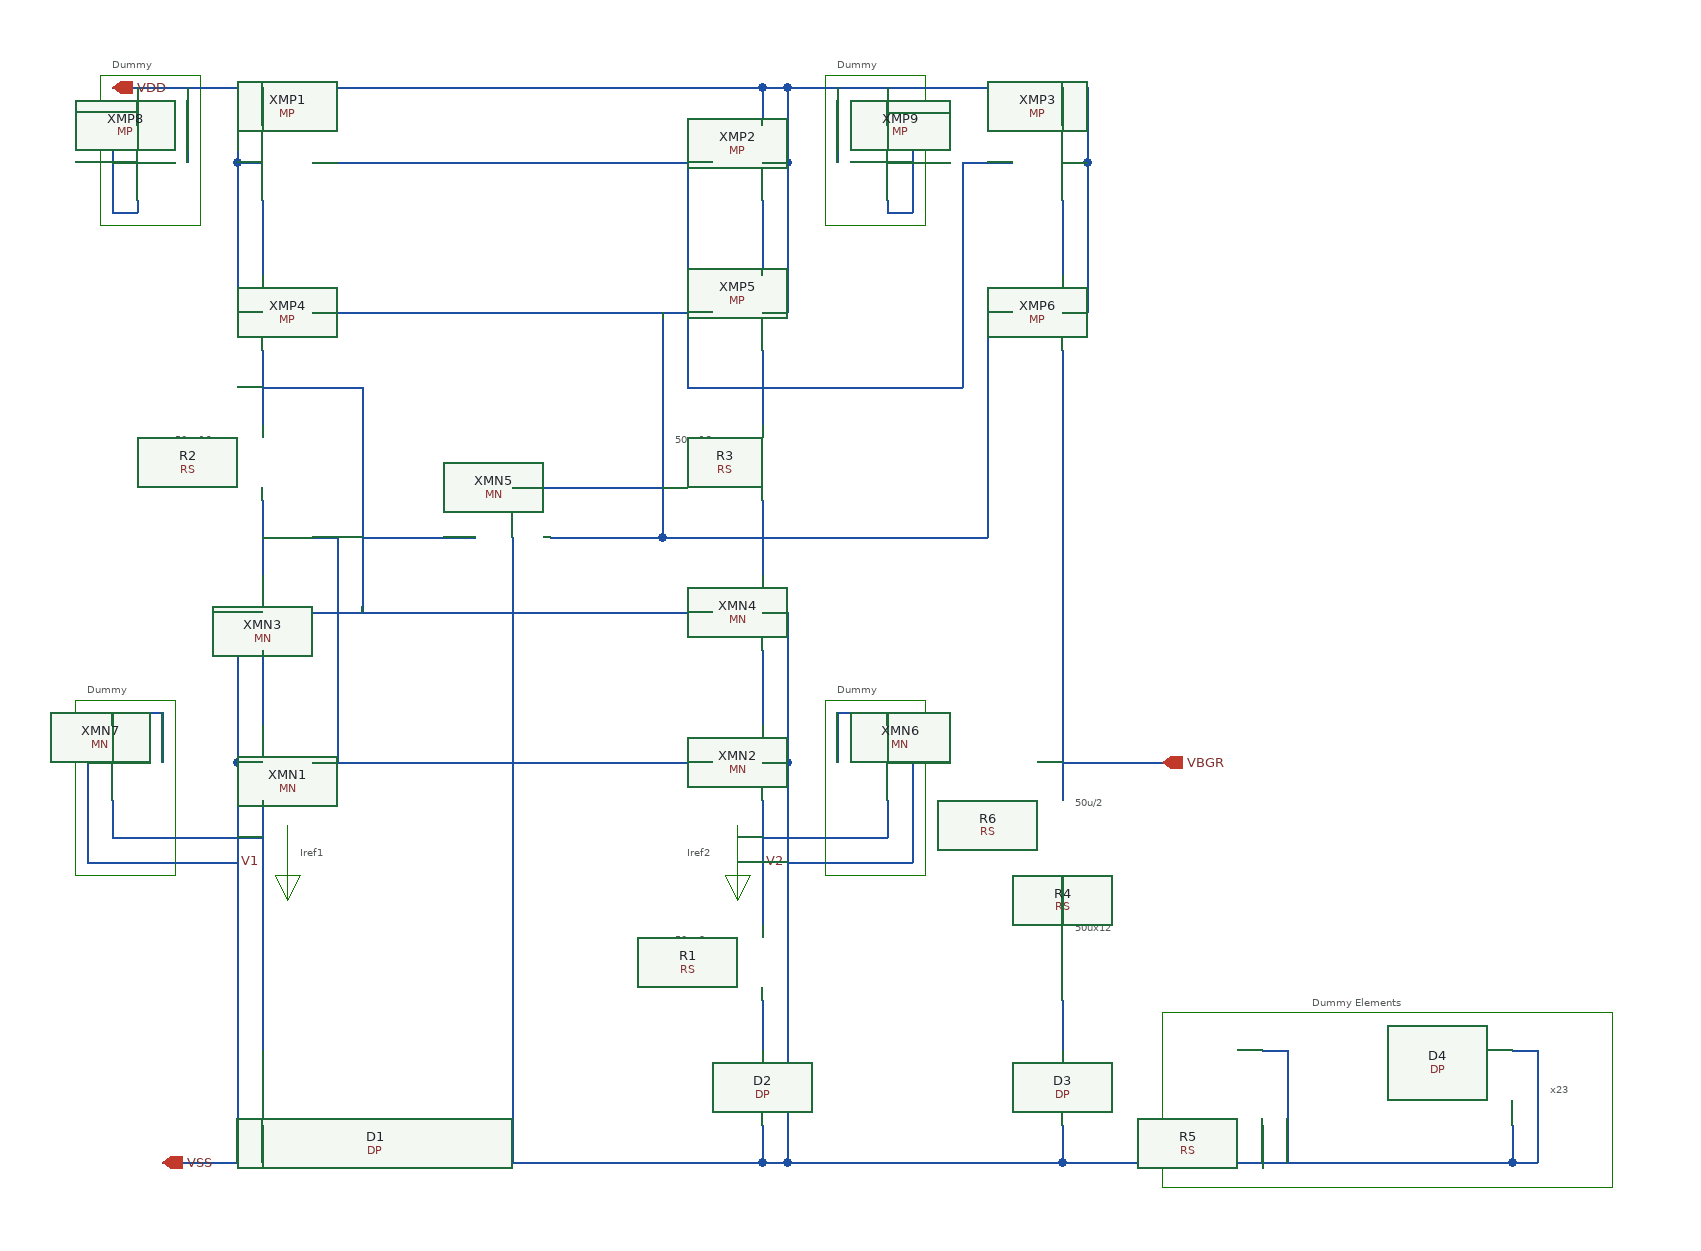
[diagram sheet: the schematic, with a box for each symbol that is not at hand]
v {xschem version=3.4.8RC file_version=1.2}
G {}
K {}
V {}
S {}
E {}
P 4 5 180 -290 180 -230 190 -250 170 -250 180 -230 {}
P 4 5 540 -290 540 -230 550 -250 530 -250 540 -230 {}
P 4 5 880 -140 880 0 1240 0 1240 -140 880 -140 {}
P 4 5 610 -390 610 -250 690 -250 690 -390 610 -390 {}
P 4 5 10 -390 10 -250 90 -250 90 -390 10 -390 {}
P 4 5 30 -890 30 -770 110 -770 110 -890 30 -890 {}
P 4 5 610 -890 610 -770 690 -770 690 -890 610 -890 {}
T {Iref1} 190 -280 0 0 0.25 0.25 {}
T {Iref2} 500 -280 0 0 0.25 0.25 {}
T {x8} 590 -90 0 0 0.25 0.25 {}
T {x8} 830 -90 0 0 0.25 0.25 {}
T {50ux2} 490 -210 0 0 0.25 0.25 {}
T {50ux16} 490 -610 0 0 0.25 0.25 {}
T {50ux16} 90 -610 0 0 0.25 0.25 {}
T {50ux12} 810 -220 0 0 0.25 0.25 {}
T {x23} 1190 -90 0 0 0.25 0.25 {}
T {Dummy Elements} 1000 -160 0 0 0.25 0.25 {}
T {Dummy} 620 -410 0 0 0.25 0.25 {}
T {Dummy} 20 -410 0 0 0.25 0.25 {}
T {Dummy} 40 -910 0 0 0.25 0.25 {}
T {Dummy} 620 -910 0 0 0.25 0.25 {}
T {50u/2} 810 -320 0 0 0.25 0.25 {}
N 560 -880 560 -850 {lab=VDD}
N 80 -880 560 -880 {lab=VDD}
N 160 -880 160 -850 {lab=VDD}
N 560 -820 580 -820 {lab=VDD}
N 580 -880 580 -820 {lab=VDD}
N 560 -880 580 -880 {lab=VDD}
N 140 -820 160 -820 {lab=VDD}
N 140 -880 140 -820 {lab=VDD}
N 200 -820 520 -820 {lab=#net1}
N 160 -310 160 -260 {lab=V1}
N 560 -310 560 -260 {lab=V2}
N 560 -340 580 -340 {lab=VSS}
N 580 -340 580 -300 {lab=VSS}
N 140 -340 160 -340 {lab=VSS}
N 140 -340 140 -300 {lab=VSS}
N 200 -340 520 -340 {lab=#net2}
N 220 -520 220 -340 {lab=#net2}
N 160 -520 220 -520 {lab=#net2}
N 500 -820 500 -780 {lab=#net1}
N 500 -780 500 -760 {lab=#net1}
N 500 -640 560 -640 {lab=#net1}
N 560 -260 560 -210 {lab=V2}
N 560 -150 560 -110 {lab=#net3}
N 160 -260 160 -110 {lab=V1}
N 560 -50 560 -20 {lab=VSS}
N 80 -20 560 -20 {lab=VSS}
N 160 -50 160 -20 {lab=VSS}
N 560 -640 720 -640 {lab=#net1}
N 720 -820 720 -640 {lab=#net1}
N 720 -820 760 -820 {lab=#net1}
N 580 -880 820 -880 {lab=VDD}
N 820 -880 820 -820 {lab=VDD}
N 800 -820 820 -820 {lab=VDD}
N 800 -880 800 -850 {lab=VDD}
N 800 -670 800 -600 {lab=VBGR}
N 160 -790 160 -730 {lab=#net4}
N 560 -790 560 -730 {lab=#net5}
N 200 -700 520 -700 {lab=#net6}
N 160 -430 160 -370 {lab=#net7}
N 560 -430 560 -370 {lab=#net8}
N 560 -460 580 -460 {lab=VSS}
N 200 -460 520 -460 {lab=#net9}
N 140 -460 160 -460 {lab=VSS}
N 560 -670 560 -610 {lab=#net1}
N 560 -700 580 -700 {lab=VDD}
N 140 -700 160 -700 {lab=VDD}
N 480 -700 480 -520 {lab=#net6}
N 480 -520 560 -520 {lab=#net6}
N 240 -640 240 -460 {lab=#net9}
N 160 -640 240 -640 {lab=#net9}
N 580 -740 580 -700 {lab=VDD}
N 140 -740 140 -700 {lab=VDD}
N 140 -460 140 -420 {lab=VSS}
N 580 -460 580 -420 {lab=VSS}
N 140 -820 140 -740 {lab=VDD}
N 580 -820 580 -740 {lab=VDD}
N 140 -420 140 -340 {lab=VSS}
N 580 -420 580 -340 {lab=VSS}
N 140 -300 140 -20 {lab=VSS}
N 580 -300 580 -20 {lab=VSS}
N 560 -20 580 -20 {lab=VSS}
N 160 -670 160 -610 {lab=#net9}
N 160 -550 160 -490 {lab=#net2}
N 560 -550 560 -490 {lab=#net6}
N 500 -760 500 -640 {lab=#net1}
N 800 -790 800 -730 {lab=#net10}
N 560 -520 740 -520 {lab=#net6}
N 800 -700 820 -700 {lab=VDD}
N 820 -820 820 -700 {lab=VDD}
N 740 -700 760 -700 {lab=#net6}
N 740 -700 740 -520 {lab=#net6}
N 800 -150 800 -110 {lab=#net11}
N 800 -50 800 -20 {lab=VSS}
N 580 -20 800 -20 {lab=VSS}
N 800 -600 800 -310 {lab=VBGR}
N 800 -340 880 -340 {lab=VBGR}
N 390 -520 480 -520 {lab=#net6}
N 360 -560 480 -560 {lab=#net6}
N 240 -520 330 -520 {lab=#net9}
N 360 -520 360 -20 {lab=VSS}
N 800 -20 1160 -20 {lab=VSS}
N 1160 -50 1160 -20 {lab=VSS}
N 1160 -110 1180 -110 {lab=VSS}
N 1180 -110 1180 -20 {lab=VSS}
N 1160 -20 1180 -20 {lab=VSS}
N 620 -380 620 -340 {lab=VSS}
N 660 -340 680 -340 {lab=VSS}
N 580 -260 680 -260 {lab=VSS}
N 80 -380 80 -340 {lab=VSS}
N 20 -340 40 -340 {lab=VSS}
N 20 -380 20 -260 {lab=VSS}
N 40 -310 40 -280 {lab=V1}
N 40 -280 160 -280 {lab=V1}
N 20 -260 140 -260 {lab=VSS}
N 40 -380 40 -370 {lab=VSS}
N 20 -380 80 -380 {lab=VSS}
N 660 -380 660 -370 {lab=VSS}
N 620 -380 680 -380 {lab=VSS}
N 680 -380 680 -260 {lab=VSS}
N 660 -310 660 -280 {lab=V2}
N 560 -280 660 -280 {lab=V2}
N 40 -880 80 -880 {lab=VDD}
N 60 -880 60 -850 {lab=VDD}
N 60 -790 60 -780 {lab=VDD}
N 40 -780 60 -780 {lab=VDD}
N 40 -860 40 -780 {lab=VDD}
N 40 -860 60 -860 {lab=VDD}
N 100 -880 100 -820 {lab=VDD}
N 40 -820 60 -820 {lab=VDD}
N 660 -880 660 -850 {lab=VDD}
N 660 -790 660 -780 {lab=VDD}
N 660 -780 680 -780 {lab=VDD}
N 680 -860 680 -780 {lab=VDD}
N 660 -860 680 -860 {lab=VDD}
N 620 -880 620 -820 {lab=VDD}
N 660 -820 680 -820 {lab=VDD}
N 960 -110 980 -110 {lab=VSS}
N 980 -110 980 -20 {lab=VSS}
N 960 -50 960 -20 {lab=VSS}
N 800 -250 800 -210 {lab=#net12}
C {MP.sym} 200 -820 0 1 {name=XMP1 model=PMOS w=20u l=4u m=4 as=0 ad=0 ps=0 pd=0 nrd=0 nrs=0}
C {MN.sym} 200 -340 0 1 {name=XMN1 model=NMOS w=10u l=4u m=4 as=0 ad=0 ps=0 pd=0 nrd=0 nrs=0}
C {MP.sym} 520 -820 0 0 {name=XMP2 model=PMOS w=20u l=4u m=4 as=0 ad=0 ps=0 pd=0 nrd=0 nrs=0}
C {MN.sym} 520 -340 0 0 {name=XMN2 model=NMOS w=10u l=4u m=4 as=0 ad=0 ps=0 pd=0 nrd=0 nrs=0}
C {devices/iopin.sym} 40 -880 0 1 {name=p1 lab=VDD}
C {devices/iopin.sym} 80 -20 0 1 {name=p2 lab=VSS}
C {MP.sym} 760 -820 0 0 {name=XMP3 model=PMOS w=20u l=4u m=4 as=0 ad=0 ps=0 pd=0 nrd=0 nrs=0}
C {devices/lab_wire.sym} 160 -260 0 0 {name=p4 sig_type=std_logic lab=V1}
C {devices/lab_wire.sym} 560 -260 0 1 {name=p5 sig_type=std_logic lab=V2}
C {MP.sym} 200 -700 0 1 {name=XMP4 model=PMOS w=20u l=1u m=4 as=0 ad=0 ps=0 pd=0 nrd=0 nrs=0}
C {MP.sym} 520 -700 0 0 {name=XMP5 model=PMOS w=20u l=1u m=4 as=0 ad=0 ps=0 pd=0 nrd=0 nrs=0}
C {MN.sym} 200 -460 0 1 {name=XMN3 model=NMOS w=10u l=1u m=4 as=0 ad=0 ps=0 pd=0 nrd=0 nrs=0}
C {MN.sym} 520 -460 0 0 {name=XMN4 model=NMOS w=10u l=1u m=4 as=0 ad=0 ps=0 pd=0 nrd=0 nrs=0}
C {MP.sym} 760 -700 0 0 {name=XMP6 model=PMOS w=20u l=1u m=4 as=0 ad=0 ps=0 pd=0 nrd=0 nrs=0}
C {devices/opin.sym} 880 -340 0 0 {name=p3 lab=VBGR}
C {MN.sym} 360 -560 1 0 {name=XMN5 model=NMOS w=4u l=4u m=1 as=0 ad=0 ps=0 pd=0 nrd=0 nrs=0}
C {RS.sym} 560 -210 0 0 {name=R1
w=4e-6
l=100e-6
R=1
model=F_RS
spiceprefix=X
tc1=0
tc2=0}
C {RS.sym} 800 -210 0 0 {name=R4
w=4e-6
l=600e-6
R=1
model=F_RS
spiceprefix=X
tc1=0
tc2=0}
C {RS.sym} 160 -610 0 0 {name=R2
w=4e-6
l=800e-6
R=1
model=F_RS
spiceprefix=X
tc1=0
tc2=0}
C {RS.sym} 560 -610 0 0 {name=R3
w=4e-6
l=800e-6
R=1
model=F_RS
spiceprefix=X
tc1=0
tc2=0}
C {RS.sym} 960 -110 0 0 {name=R5
w=4e-6
l=50e-6
R=1
m=6
model=F_RS
spiceprefix=X
tc1=0
tc2=0}
C {MN.sym} 620 -340 0 0 {name=XMN6 model=NMOS w=10u l=4u m=2 as=0 ad=0 ps=0 pd=0 nrd=0 nrs=0}
C {MN.sym} 80 -340 0 1 {name=XMN7 model=NMOS w=10u l=4u m=2 as=0 ad=0 ps=0 pd=0 nrd=0 nrs=0}
C {DP.sym} 160 -50 2 0 {name=D1
model=DP
w=3.6u
l=3.6u
a="expr_eng( @w * @l )"
p="expr_eng( 2 * ( @w + @l ) )"
spiceprefix=D
m=1}
C {DP.sym} 560 -50 2 0 {name=D2
model=DP
w=3.6u
l=3.6u
a="expr_eng( @w * @l )"
p="expr_eng( 2 * ( @w + @l ) )"
spiceprefix=D
m=8}
C {DP.sym} 800 -50 2 0 {name=D3
model=DP
w=3.6u
l=3.6u
a="expr_eng( @w * @l )"
p="expr_eng( 2 * ( @w + @l ) )"
spiceprefix=D
m=8}
C {DP.sym} 1160 -50 2 0 {name=D4
model=DP
w=3.6u
l=3.6u
a="expr_eng( @w * @l )"
p="expr_eng( 2 * ( @w + @l ) )"
spiceprefix=D
m=23}
C {MP.sym} 100 -820 0 1 {name=XMP8 model=PMOS w=20u l=4u m=1 as=0 ad=0 ps=0 pd=0 nrd=0 nrs=0}
C {MP.sym} 620 -820 0 0 {name=XMP9 model=PMOS w=20u l=4u m=1 as=0 ad=0 ps=0 pd=0 nrd=0 nrs=0}
C {RS.sym} 800 -310 0 0 {name=R6
w=4e-6
l=50e-6
R=1
m=2
model=F_RS
spiceprefix=X
tc1=0
tc2=0}
